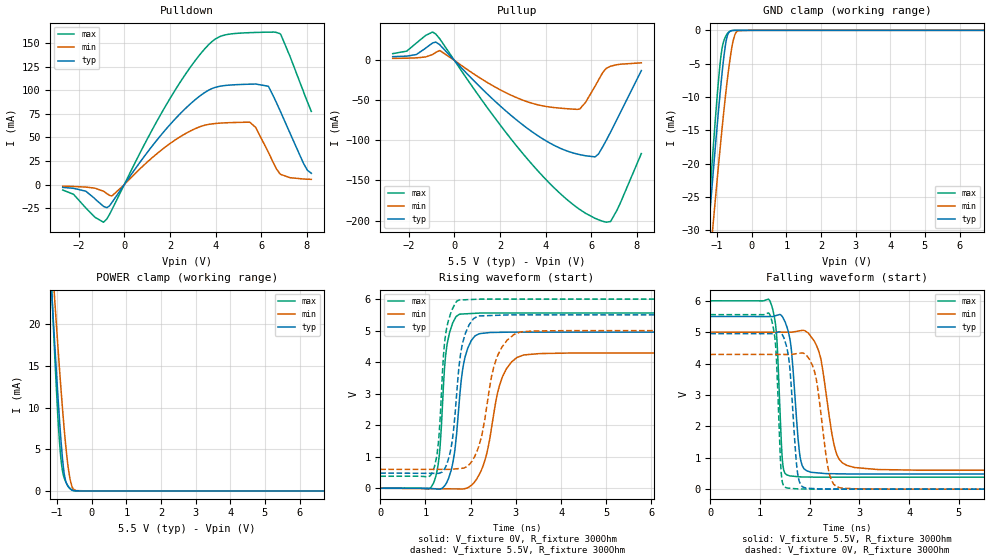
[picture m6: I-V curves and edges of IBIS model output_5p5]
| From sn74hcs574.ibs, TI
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|   output_5p5 Model
[Model]   output_5p5
Model_type   I/O
Polarity   Non-Inverting
Enable   Active-High
Vmeas = 2.75
Vref = 0
Cref = 2pF
Rref = 100000
Vinl = 2.45
Vinh = 3.0
|   typ   min   max
C_comp   0.801pF   0.769pF   0.801pF
| Where Nom  PVT is Nominal Process, 5.5V, 27C
|   Fast PVT is Strong Process,  6.0V, -55C
|   Slow PVT is Weak Process,   5.0V, 150C
[Voltage Range]   5.5   5   6
|Junction Temperature
[Temperature Range]   27   150   -55
[Pullup Reference]   5.5   5   6
[Pulldown Reference]   0   0   0
[Power Clamp Reference]   5.5   5   6
[GND Clamp Reference]   0   0   0
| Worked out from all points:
|   slope of the pulldown table from 0 to 0.825 V, typ, clamps not added: 29.3 ohm
|   slope of the pullup table from 0 to 0.825 V, typ, clamps not added: 33.6 ohm
|   GND clamp passes 1 mA (typ) near -0.72 V on its own axis
|   POWER clamp passes 1 mA (typ) near -0.74 V on its own axis
|   falling waveform, V_fixture 5.5V, R_fixture 300Ohm: 20-80 % time 147ps typ, 254ps min, 93.5ps max; typ from 5.5 V to 0.481 V
|   rising waveform, V_fixture 0V, R_fixture 300Ohm: 20-80 % time 219ps typ, 371ps min, 157ps max; typ from 0 V to 4.95 V
|   rising waveform, V_fixture 5.5V, R_fixture 300Ohm: 20-80 % time 217ps typ, 364ps min, 156ps max; typ from 0.481 V to 5.5 V
|   falling waveform, V_fixture 0V, R_fixture 300Ohm: 20-80 % time 131ps typ, 210ps min, 86.5ps max; typ from 4.95 V to 0 V
[Pulldown]
|   Voltage   I(typ)   I(min)   I(max)
-2.7V     -3.055mA   -1.706mA   -5.778mA
-1.686V   -7.04mA    -2.68mA    -24.81mA
-901.5mV  -23.23mA   -7.206mA   -39.81mA
-541.8mV  -18.99mA   -12.08mA   -26.61mA
2.325V    71.94mA    48.73mA    103.7mA
3.546V    97.82mA    62.97mA    144.3mA
4.309V    104.6mA    65.26mA    157.8mA
5.508V    106.3mA    65.99mA    160.9mA
6.314V    104.2mA    34.33mA    161.5mA
6.827V    78.5mA     11.4mA     159.8mA
7.862V    22.23mA    5.883mA    97.97mA
8.2V      11.95mA    5.526mA    77.53mA
[GND Clamp]
|   Voltage   I(typ)   I(min)   I(max)
-2.7V     -128.8mA   -126.7mA   -143.3mA
-1.37V    -37.73mA   -43.99mA   -36.6mA
-1.25V    -29.89mA   -36.83mA   -27.5mA
-1.119V   -21.55mA   -29.17mA   -17.93mA
-988.7mV  -13.58mA   -21.72mA   -9.11mA
-901.5mV  -8.626mA   -16.95mA   -4.285mA
-836.1mV  -5.272mA   -13.52mA   -2.102mA
-759.8mV  -2.144mA   -9.779mA   -950.2uA
-650.8mV  -239.3uA   -5.101mA   -180.5uA
-541.8mV  -18.61uA   -1.605mA   -12.31uA
-378.3mV  -181.5nA   -43.9uA    -26.91nA
8.2V      0A         0A         0A
[Pullup]
|   Voltage   I(typ)   I(min)   I(max)
-2.7V     4.483mA    2.329mA    8.237mA
-2.09V    5.115mA    2.555mA    11.35mA
-1.665V   7.128mA    2.966mA    21.42mA
-814.3mV  22.67mA    9.734mA    32.78mA
-629mV    19.08mA    12.01mA    26.41mA
2.02V     -57.18mA   -36.97mA   -81.05mA
3.851V    -97.59mA   -56.78mA   -143.8mA
5.486V    -117.6mA   -60.87mA   -185.9mA
6.173V    -120.6mA   -32.4mA    -197.2mA
6.511V    -107.8mA   -15.2mA    -200.9mA
6.859V    -89.22mA   -7.335mA   -201mA
8.2V      -12.85mA   -3.236mA   -116.5mA
[POWER Clamp]
|   Voltage   I(typ)   I(min)   I(max)
-2.7V     153.5mA    137.3mA    203.1mA
-1.207V   27.35mA    31.53mA    28.8mA
-1.098V   19.47mA    24.59mA    18.65mA
-1.054V   16.42mA    21.87mA    14.81mA
-966.9mV  10.6mA     16.6mA     7.948mA
-879.7mV  5.467mA    11.64mA    3.382mA
-814.3mV  2.584mA    8.244mA    1.77mA
-759.8mV  1.253mA    5.722mA    1.163mA
-672.6mV  471.3uA    2.518mA    502uA
-574.5mV  116.9uA    531.2uA    97.83uA
-29.5mV   0A         0A         0A
8.2V      0A         0A         0A
[Ramp]
R_load = 300
|   typ   min   max
dV/dt_r   2.97105/2.17555e-10   2.57479/3.67059e-10   3.33531/1.56007e-10
dV/dt_f   3.01142/1.46082e-10   2.63979/2.53109e-10   3.37171/9.34991e-11
[Falling Waveform]
V_fixture = 5.5V
V_fixture_min = 5V
V_fixture_max = 6V
R_fixture = 300Ohm
C_fixture = 0F
|   Time   V(typ)   V(min)   V(max)
0s        5.5V       5V         6V
1.2ns     5.498V     4.999V     5.998V
1.333ns   5.534V     4.999V     4.935V
1.459ns   5.47V      4.999V     790.4mV
1.596ns   4.83V      4.999V     423.3mV
1.802ns   1.082V     5.044V     392.6mV
2.03ns    538.6mV    4.85V      385mV
2.53ns    490.3mV    1.174V     380.9mV
2.892ns   482.2mV    694.2mV    380.9mV
15ns      481mV      600.3mV    380.5mV
[Rising Waveform]
V_fixture = 0V
V_fixture_min = 0V
V_fixture_max = 0V
R_fixture = 300Ohm
C_fixture = 0F
|   Time   V(typ)   V(min)   V(max)
0s        8.717uV    13uV       4.66uV
1.176ns   -12.93mV   -14.35mV   159.9mV
1.307ns   -28.44mV   -15.95mV   1.069V
1.473ns   193.6mV    -17.98mV   4.517V
1.638ns   1.082V     -19.99mV   5.34V
1.753ns   2.847V     -21.4mV    5.52V
2.097ns   4.836V     219.3mV    5.548V
2.696ns   4.947V     3.509V     5.558V
3.164ns   4.951V     4.223V     5.558V
15ns      4.952V     4.291V     5.559V
[Rising Waveform]
V_fixture = 5.5V
V_fixture_min = 5V
V_fixture_max = 6V
R_fixture = 300Ohm
C_fixture = 0F
|   Time   V(typ)   V(min)   V(max)
0s        481mV      600.3mV    380.5mV
1.156ns   473.5mV    599.4mV    515.8mV
1.283ns   472.7mV    599.3mV    1.408V
1.448ns   684.1mV    599.1mV    4.9V
1.596ns   1.55V      604.6mV    5.685V
1.737ns   3.786V     624.4mV    5.967V
2.064ns   5.379V     943.6mV    5.99V
2.581ns   5.485V     4.153V     6V
3.105ns   5.499V     4.958V     6V
15ns      5.5V       5V         6V
[Falling Waveform]
|Gnd
V_fixture = 0V
V_fixture_min = 0V
V_fixture_max = 0V
R_fixture = 300Ohm
C_fixture = 0F
|   Time   V(typ)   V(min)   V(max)
0s        4.952V     4.291V     5.559V
1.2ns     4.95V      4.29V      5.55V
1.318ns   4.979V     4.29V      4.488V
1.434ns   4.963V     4.29V      406.5mV
1.546ns   4.464V     4.29V      36.17mV
1.748ns   616.7mV    4.319V     9.858mV
1.915ns   38.68mV    4.291V     4.921mV
2.402ns   5.357mV    450.9mV    418.4uV
2.614ns   2.096mV    41.77mV    411.4uV
15ns      8.869uV    13.25uV    4.776uV
